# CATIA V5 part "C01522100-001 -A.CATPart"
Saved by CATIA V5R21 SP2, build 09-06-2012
Part number: C01522100-001
Revision: ---
Description: PROPRIETARY NOTICE (do not delete / modify)  ***************************************************************************************************  LA SOCIETE EN COMMANDITE  AIRBUS CANADA  ("AIRBUS CANADA")  PAR  L'INTERMEDIAIRE  DE  SES  DIVISIONS  ET/OU  FILIALES  CORPORATIVES,  FOURNIT  LES PRESENTES  INFORMATIONS  AU  GOUVERNEMENT  A  TITRE CONFIDENTIEL. CES  INFORMATIONS ONT UNE TENEUR CONFIDENTIELLE,  AVEC DROITS DE PROPRIETE,  ET NOUS LES CONSIDERONS  EXCLUS  DE   L'APPLICATION  DE  LA LOI SUR L'ACCES A L'INFORMATION  (CANADA),  LES  LOIS  SUR  L'ACCES  A  L'INFORMATION  EUROPEENNES,  LE FREEDOM OF INFORMATION ACT (ETATS-UNIS) ET D'AUTRES LOIS SEMBLABLES. ELLES  PEUVENT  AUSSI  CONSTITUER DES SECRETS INDUSTRIELS DE NOTRE SOCIETE OU DE TIERCES PARTIES. LA DIVULGATION  PUBLIQUE  DE CES  INFORMATIONS NUIRAIT A AIRBUS CANADA OU A DES TIERCES PARTIES.  CES INFORMATIONS PEUVENT EGALEMENT CONTENIR  DES DONNEES QUI SONT CONTROLEE PAR DES LOIS DE CONTROLE DES EXPORTATIONS DU CANADA, L’EUROPE OU LES  ETATS-  UNIS. TOUTE EXPORTATION OU REEXPORTATION DE DONNEES CONTROLEES SANS AUTORISATION EST STRICTEMENT INTERDITE.  TOUTE INTENTION DE LES DIVULGUER EN TOUT OU EN PARTIE DEVRA ETRE SIGNIFIEE A L'AVANCE ET PAR ECRIT AU VICE-  PRESIDENT, SERVICES JURIDIQUES ET CONFORMITE ET SECRETAIRE CORPORATIF D'AIRBUS CANADA.    AIRBUS CANADA LIMITED PARTNERSHIP  ("AIRBUS CANADA"),  BY ITS AFFILIATES AND/OR SUBSIDIARIES, PROVIDES THIS  INFORMATION TO THE GOVERNMENT IN CONFIDENCE. THIS IS PROPRIETARY CONFIDENTIAL INFORMATION WHICH WE CONSIDER  EXCLUDED  FROM  THE  APPLICATION OF THE ACCESS TO INFORMATION ACT (CANADA),  THE FREEDOM OF INFORMATION ACT  (U.S.A.),  THE ACCESS TO INFORMATION LAWS IN EUROPE, AND OTHER SIMILAR LEGISLATION. AND MAY ALSO CONSTITUTE  TRADE SECRETS OF OUR  COMPANY OR THIRD PARTIES.  PUBLIC  RELEASE  OF  THIS INFORMATION  WOULD BE HARMFUL TO  AIRBUS CANADA OR THIRD PARTIES.  THIS  INFORMATION  MAY  ALSO  CONTAIN DATA THAT IS CONTROLLED BY CANADIAN,  EUROPEAN, OR U.S.A. EXPORT CONTROL LAWS. ANY UNAUTHORIZED EXPORT OR RE-EXPORT OF ANY EXPORT CONTROLLED DATA  IS STRICTLY PROHIBITED  ANY INTENTION TO DISCLOSE SUCH INFORMATION,  OR  PART THEREOF,  MUST BE NOTIFIED IN  ADVANCE AND IN WRITING TO THE VICE PRESIDENT, LEGAL AND COMPLIANCE AND CORPORATE SECRETARY OF AIRBUS CANADA.        LES RENSEIGNEMENTS,  LES DONNEES  ET  DESSINS  TECHNIQUES  DIVULGUES  DANS  LES PRESENTES SONT LA PROPRIETE  EXCLUSIVE DE LA SOCIETE EN COMMANDITE AIRBUS CANADA ("AIRBUS CANADA") OU COMPORTENT DES DROITS DE PROPRIETE  APPARTENANT  A  AUTRUI ET NE PEUVENT ETRE DIVULGUES  A  QUICONQUE  NI  UTILISES PAR QUI QUE CE SOIT SANS LE  CONSENTEMENT  ECRIT  D’AIRBUS  CANADA.  LE DETENTEUR DES  PRESENTES  S'ENGAGE, DANS TOUTES CIRCONSTANCES, A  GARDER CONFIDENTIELS LES DONNEES ET DESSINS TECHNIQUES QU'ELLES CONTIENNENT.   CE QUI PRECEDE NE S'APPLIQUE  PAS  AUX PERSONNES  QUI  ONT DES DROITS DE PROPRIETE SUR CES RENSEIGNEMENTS,  DONNEES TECHNIQUES ET DESSINS  DANS LA MESURE OU CES DROITS EXISTENT.    THE INFORMATION,  TECHNICAL DATA  AND  DESIGNS DISCLOSED HEREIN ARE THE EXCLUSIVE PROPERTY OF AIRBUS CANADA  LIMITED PARTNERSHIP  ("AIRBUS CANADA")  OR  CONTAIN PROPRIETARY RIGHTS OF OTHERS  AND ARE NOT TO BE USED OR  DISCLOSED  TO  OTHERS WITHOUT THE WRITTEN CONSENT OF AIRBUS CANADA.  THE RECIPIENT OF THIS DOCUMENT, BY ITS  RETENTION  AND  USE  AGREES TO  HOLD  IN  CONFIDENCE  THE  TECHNICAL DATA AND DESIGNS CONTAINED HEREIN. THE  FOREGOING SHALL NOT APPLY TO PERSONS HAVING PROPRIETARY RIGHTS TO SUCH INFORMATION,  TECHNICAL DATA OR SUCH  DESIGNS TO THE EXTENT THAT SUCH RIGHTS EXIST.    Copyright 2020 Airbus Canada Limited Partnership. All Rights Reserved.  ***********************************
Property "Title": "CRANK, VENT PNL, FWD SVCE DR"
Property "Dataset Type": "DETAIL"
Property "Supplier Name And CAGE Code": "AIRBUS CANADA LIMITED PARTNERSHIP L0J48"
Property "Major Supplier Code": "LP"
Property "3D Only": "Y"
Property "Material Form": "PLATE"
Property "Finish Code": "T002"
Property "PCCN": "2"
Property "Organization": "DESIGN"
Property "Design Authority Program": "BD-500"
Property "Color Coded": "N"
Property "Thickness": 1.25
Property "Inside Diameter": 0
Property "Outside Diameter": 0
Property "Length": 0
Property "Width": 0
Property "Wall": 0
Property "Wire Gauge": "-"
Property "Alloy": "6AL-4V"
Property "Final Condition": "ANL"
Property "Density": "N/A"
Property "Form": "N/A"
Property "Grade/Composition": "N/A"
Property "Material Class": "N/A"
Property "Mesh Cell Size": "N/A"
Property "Standard Spec Die": "N/A"
Property "Type": "N/A"
Property "Style": "N/A"
Property "MFG Process": "MACHINED"
Property "Material Specification Production": "AMS4911"
Property "Material Description Production": "TITANIUM"
Property "Dimensions": "DIMENSIONS ARE IN INCHES"
Property "Roughness": "ALL MACHINED SURFACES 125 Ra MAX"
Property "Eng. Tolerances": "LINEAR .XX= +/-.03; .XXX= +/-.010; ANGULAR= +/-0.5 DEG"
Property "Tool Design Tolerances": "LINEAR .X= +/-.06; .XX= +/-.015; .XXX= +/-.005; .XXXX= +/-.001; ANGULAR= +/-0.5 DEG"
Property "Project": "BA"
Publications: "PartBody", "REFERENCE PLANE", "REFERENCE ORIENTATION", "REFERENCE AXIS", "Extract.1_Datum_A", "Extract.1_Datum_B", "Extract.1_Datum_C"
Material "TI-6AL-4V": density 4428.78 kg/m3, Young's modulus 1.11695e+11 Pa, Poisson ratio 0.31
Bounding box of the stored display mesh (mm): x -10.439 to 116.078, y -11.089 to 11.089, z -67.945 to 18.498
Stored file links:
  C:\Users\CQQZ006\Desktop\A220钢钛件\舱门\C01522100-001\C01522100-001 -A.CATPart

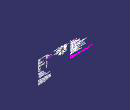
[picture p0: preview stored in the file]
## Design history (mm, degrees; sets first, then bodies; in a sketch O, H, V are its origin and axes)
Parameters
  LENGTH = 15.875 mm
  LENGTH = 15.875 mm
  LENGTH = 20.6807 mm
Part_3D_Annotations1 "CATTPSSet"
AxisSystem1 "Absolute Axis System": origin (0, 0, 0), X (1, 0, 0), Y (0, 1, 0), Z (0, 0, 1)
Set1 "Pilot_Holes"
  Set2 "1/4"
    Set3 "Copied From C01512208-001"
      Point1 "Fix Point 1": stored without definition
      Line1 "Fix Orientation 1": stored without definition
      Point2 "Fix Point 2": stored without definition
      Line2 "Fix Orientation 2": stored without definition
Set4 "Master_Geometry"
  Plane1: type Offset, RefPlane yz-plane, Offset 10.4394, reversed
  Plane2: type Offset, RefPlane Plane1, Offset 113.538
  Plane3: type Offset, RefPlane yz-plane, Offset 10.4394
  Plane4: type Offset, RefPlane Plane2, Offset 21.59
  Point3: type Center, Curve edge [end face of Pad1 | face of Pocket1 from Sketch2.A2]
  Point4: type Center, Curve edge [end face of Pad1 | face of Pocket1 from Sketch2.A1]
  Point5: type Center, Curve edge [face of Groove1 from Sketch6.L1 | face of Groove1 from Sketch6.L10]
Set5 "References"
  Line3 "REFERENCE ORIENTATION": type PtDir, RefPoint Point3, Direction Plane1, Start -6.35, End 27.94
  Plane5 "REFERENCE PLANE": type Offset, RefPlane face of Pocket4 from Sketch5.L2, Offset 1.5113, reversed
  Line4 "REFERENCE AXIS": type PtPt, FirstPoint Point5, SecondPoint Point4
Set6 "Geometrical Set for 3D Annotations"
  Set7 "No Show Geometry"
    Extract1 "Extract.1_Datum_A": ExtractElem face of Groove1 from Sketch6.L12
    Extract2 "Extract.1_Datum_B": ExtractElem end face of Pad1
    Extract3 "Extract.1_Datum_C": ExtractElem face of Pad1 from Sketch1.A3
  Set8 "Surfaces for 3D Annotations"
    Plane6: type Offset, RefPlane face of Groove1 from Sketch6.L2, Offset 2.8194, reversed
    Split1: ToCut {extract ExtractElem face of Groove1 from Sketch6.L1}, Cutting Plane6
Body1 "PartBody" (main body)
  Sketch1 on yz-plane, origin (0, 0, 0), H (0, 1, 0), V (0, 0, 1)
    arc A1 centre (0, 0) radius 11.43 from (11.4273, -0.2485) to (-11.4273, -0.2485) ccw
    construction line L1 (0, 0) -> (0, -58.42)
    arc A2 centre (0, -58.42) radius 10.16 from (-10.1576, -58.6409) to (10.1576, -58.6409) ccw
    line L2 (-11.4273, -0.2485) -> (-10.1576, -58.6409)
    line L3 (11.4273, -0.2485) -> (10.1576, -58.6409)
    point P5 (11.4273, -0.2485)
    circle A3 centre (0, -58.42) radius 4.7625
    point P6 (11.4273, -0.2485)
    length L1 = 58.42
    radius A2 = 10.16
    radius A1 = 11.43
    radius A3 = 4.7625
    tangency: L2 A2, L2 A1, L3 A2, L3 A1
    coincidence: P5 P6, L1 V
  Pad1: profile Sketch1, direction (1, 0, 0), up to Plane1, opposite side up to Plane4
  Body2
    Sketch2 on yz-plane, origin (0, 0, 0), H (0, 1, 0), V (0, 0, 1)
      arc A1 centre (0, 0) radius 10.6045 from (10.6027, -0.196) to (-10.6027, -0.196) ccw
      construction line L1 (0, 0) -> (0, -58.42)
      arc A2 centre (0, -58.42) radius 9.525 from (-9.5234, -58.596) to (9.5234, -58.596) ccw
      line L2 (-10.6027, -0.196) -> (-9.5234, -58.596)
      line L3 (10.6027, -0.196) -> (9.5234, -58.596)
      point P5 (10.6027, -0.196)
      point P6 (10.6027, -0.196)
      circle A3 centre (0, 0) radius 101.6
      length L1 = 58.42
      radius A2 = 9.525
      radius A1 = 10.6045
      radius A3 = 101.6
      tangency: L2 A2, L2 A1, L3 A2, L3 A1
      coincidence: P5 P6, L1 V
    Pocket1: profile Sketch2, direction (-1, 0, 0), length 19.05, mirrored extent
  Assemble1: tool Body2
  Body3
    Sketch3 on yz-plane, origin (0, 0, 0), H (0, 1, 0), V (0, 0, 1)
      circle A1 centre (0, 0) radius 11.43
      reference projected arc E1 centre (0, 0) radius 11.43 from (11.4297, -0.0893) to (-11.4297, -0.0893) ccw from Sketch1.A1
      circle A2 centre (0, 0) radius 101.6
      radius A2 = 101.6
      coincidence: A1 E1
    Pocket2: profile Sketch3, direction (-1, 0, 0), up to Plane3, opposite side up to Plane4
    Fillet1: radius 2.286, on edge [face of Pocket2 from Sketch3.A1 | end face of Pocket2]
  Assemble2: tool Body3
  Body4
    Sketch4 on yz-plane, origin (0, 0, 0), H (0, 1, 0), V (0, 0, 1)
      arc A1 centre (0, 0) radius 16.6827 from (-8.3066, -14.4677) to (8.3066, -14.4677) ccw
      reference projected arc E1 centre (0, 0) radius 11.43 from (11.4291, -0.1429) to (-11.4291, -0.1429) ccw from Sketch1.A1
      line L1 (7.7994, -41.91) -> (8.3066, -14.4677)
      line L2 (-7.7994, -41.91) -> (-8.3066, -14.4677)
      line L3 (-7.7994, -41.91) -> (7.7994, -41.91)
      reference projected point E2 (0, -58.42) from axis of face of Pad1 from Sketch1.A3
      reference intersected line E3 (9.5242, -58.5494) -> (10.6036, -0.1448) from face of Pocket1 from Sketch2.L3
      reference intersected line E4 (-10.6036, -0.1448) -> (-9.5242, -58.5494) from face of Pocket1 from Sketch2.L2
      distance E2 L3 = 16.51
      distance E3 L1 = 2.032
      distance L2 E4 = 2.032
      radius A1 = 16.6827
      concentricity: A1 E1
      horizontal: L3 H
    Pocket3: profile Sketch4, direction (-1, 0, 0), length 12.7, opposite side length -1.016
    Mirror1: of the body so far, about yz-plane
    Fillet2: radius 7.112, on edge [face of Pocket3 from Sketch4.L1 | face of Pocket3 from Sketch4.A1]; edge [face of Pocket3 from Sketch4.A1 | face of Pocket3 from Sketch4.L2]; edge [face of Mirror1 | face of Mirror1] (x4); edge [face of Pocket3 from Sketch4.L3 | face of Pocket3 from Sketch4.L1]; edge [face of Pocket3 from Sketch4.L2 | face of Pocket3 from Sketch4.L3]
    Fillet3: radius 2.286, on edge [face of Pocket3 from Sketch4.L1 | start face of Pocket3]; edge [face of Mirror1 | face of Mirror1]
  Assemble3: tool Body4
  Body5
    Sketch5 on zx-plane, origin (0, 0, 0), H (-1, 0, 0), V (0, 0, 1)
      line L1 (5.8674, -71.12) -> (-5.8674, -71.12)
      line L2 (-5.8674, -71.12) -> (-5.8674, -44.45)
      line L3 (-5.8674, -44.45) -> (5.8674, -44.45)
      line L4 (5.8674, -44.45) -> (5.8674, -71.12)
      reference intersected line E1 through (10.4394, 0) direction (0, -1) from end face of Pad1
      reference intersected line E2 through (-10.4394, 0) direction (0, -1) from end face of Pocket2
      reference intersected line E3 (-1.27, -41.91) -> (-12.7, -41.91) from face of Mirror1
      reference projected line E4 through (0, -58.42) direction (-1, 0) from axis of face of Pad1 from Sketch1.A3
      distance L4 E1 = 4.572
      distance E2 L2 = 4.572 {= Sketch5.distance(L4 E1)}
      distance L3 E3 = 2.54
      distance L1 E4 = 12.7
      horizontal: L1 H, L3 H
      vertical: L2 V, L4 V
    Pocket4: profile Sketch5, direction (0, -1, 0), length 12.7, mirrored extent
    Fillet4: radius 3.81, on edge [face of Pocket4 from Sketch5.L4 | face of Pocket4 from Sketch5.L3]; edge [face of Pocket4 from Sketch5.L3 | face of Pocket4 from Sketch5.L2]
  Assemble4: tool Body5
  Body6
    Sketch6 on zx-plane, origin (0, 0, 0), H (-1, 0, 0), V (0, 0, 1)
      line L1 (-116.078, 7.1438) -> (-103.632, 7.1438)
      line L2 (-103.378, 7.3978) -> (-103.378, 11.0947)
      line L3 (-10.4394, 17.78) -> (-137.3886, 17.78)
      axis line L4 (30.4475, 0) -> (-177.396, 0)
      reference projected line E1 through (0, 0) direction (-1, 0) from axis of face of Pad1 from Sketch1.A1
      line L5 (-116.078, 4.1021) -> (-99.568, 4.1021)
      point P4 (-99.568, 4.1021)
      line L6 (-99.568, 4.1021) -> (-97.8119, 7.1438)
      line L7 (-97.8119, 7.1438) -> (10.4394, 7.1438)
      line L8 (-10.4394, 17.78) -> (-10.4394, 12.8905)
      line L9 (-137.3886, 17.78) -> (-137.3886, 0)
      point P6 (-137.3886, 0)
      line L10 (-116.078, 7.1438) -> (-116.078, 4.1021)
      reference intersected line E2 through (-124.6886, 0) direction (0, -1) from Plane4
      construction line L11 (-37.8136, -7.1438) -> (7.3442, -7.1438)
      line L12 (-103.378, 11.0947) -> (-38.1, 11.0947)
      arc A1 centre (-34.6055, 23.3045) radius 12.7 from (-38.1, 11.0947) to (-34.6055, 10.6045) ccw
      point P12 (-38.1, 11.0947)
      construction line L13 (-86.5944, -11.0947) -> (-53.8682, -11.0947)
      line L14 (-34.6055, 10.6045) -> (-12.7254, 10.6045)
      construction line L15 (-26.859, -10.6045) -> (-5.1472, -10.6045)
      construction line L16 (-40.132, 12.9562) -> (-40.132, 2.6101)
      reference intersected line E3 through (-10.4394, 0) direction (0, -1) from end face of Pocket2
      arc A2 centre (-12.7254, 12.8905) radius 2.286 from (-12.7254, 10.6045) to (-10.4394, 12.8905) ccw
      line L17 (10.4394, 7.1438) -> (10.4394, 0)
      point P26 (10.4394, 0)
      line L18 (10.4394, 0) -> (-137.3886, 0)
      reference intersected line E4 through (10.4394, 0) direction (0, -1) from end face of Pad1
      arc A3 centre (-103.632, 7.3978) radius 0.254 from (-103.632, 7.1438) to (-103.378, 7.3978) ccw
      distance L1 E1 = 7.1438
      angle L6 L4 = 60
      distance L5 L4 = 4.1021
      distance L2 P4 = 3.81 (reference)
      distance E2 L9 = 12.7
      distance L4 L3 = 17.78
      distance L2 L10 = 12.7
      distance L2 P4 = 3.81
      distance L2 V = 103.378
      distance L7 L11 = 14.2875
      distance L13 L12 = 22.1894
      radius A1 = 12.7
      distance L14 L15 = 21.209
      distance P12 L16 = 2.032
      radius A2 = 2.286
      distance P12 V = 38.1
      distance L12 L7 = 3.951 (reference)
      distance L7 L14 = 3.4608 (reference)
      distance L12 L14 = 0.4902 (reference)
      radius A3 = 0.254
      horizontal: L1 H, L3 H, L5 H, L7 H, L11 H, L12 H, L13 H, L15 H, L18 H
      vertical: L2 V, L8 V, L9 V, L10 V, L16 V, L17 V
      coincidence: L4 H, P6 L4, E3 L8, P26 L4, E4 L17
      symmetry: L7 L11 L4, L12 L13 H, L15 L14 H
      tangency: L14 A1, A2 L14, A2 L8, A3 L1, A3 L2
    Groove1: profile Sketch6, axis Sketch6.L4, angle 360
  Assemble5: tool Body6
  Sketch7 on end face of Pad1, origin (-10.4394, -1.5, -50.9753), H (0, 1, 0), V (0, 0, -1)
    point P1 (1.5, 7.4447)
    reference projected circle E1 centre (1.5, 7.4447) radius 4.7625 from edge [face of Pad1 from Sketch1.A3 | end face of Pad1]
    concentricity: E1 P1
  Hole1: placed by Sketch7, at (-10.4394, 0, -58.42) direction (1, 0, 0), diameter 12.6987, through (limit type 6)
  Body7
    Sketch8 on zx-plane, origin (0, 0, 0), H (-1, 0, 0), V (0, 0, 1)
      circle A1 centre (-112.268, 0) radius 1.524
      point P1 (-112.268, 0)
      reference intersected line E1 through (-116.078, 0) direction (0, -1) from face of Groove1 from Sketch6.L10
      radius A1 = 1.524
      distance P1 E1 = 3.81
      coincidence: P1 H
    Pocket5: profile Sketch8, direction (0, -1, 0), length 19.05, mirrored extent
  Assemble6: tool Body7
  Chamfer1: length 1.016, angle 45, on edge [face of Groove1 from Sketch6.L1 | face of Groove1 from Sketch6.L10]; edge [face of Groove1 from Sketch6.L12 | face of Groove1 from Sketch6.L2]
